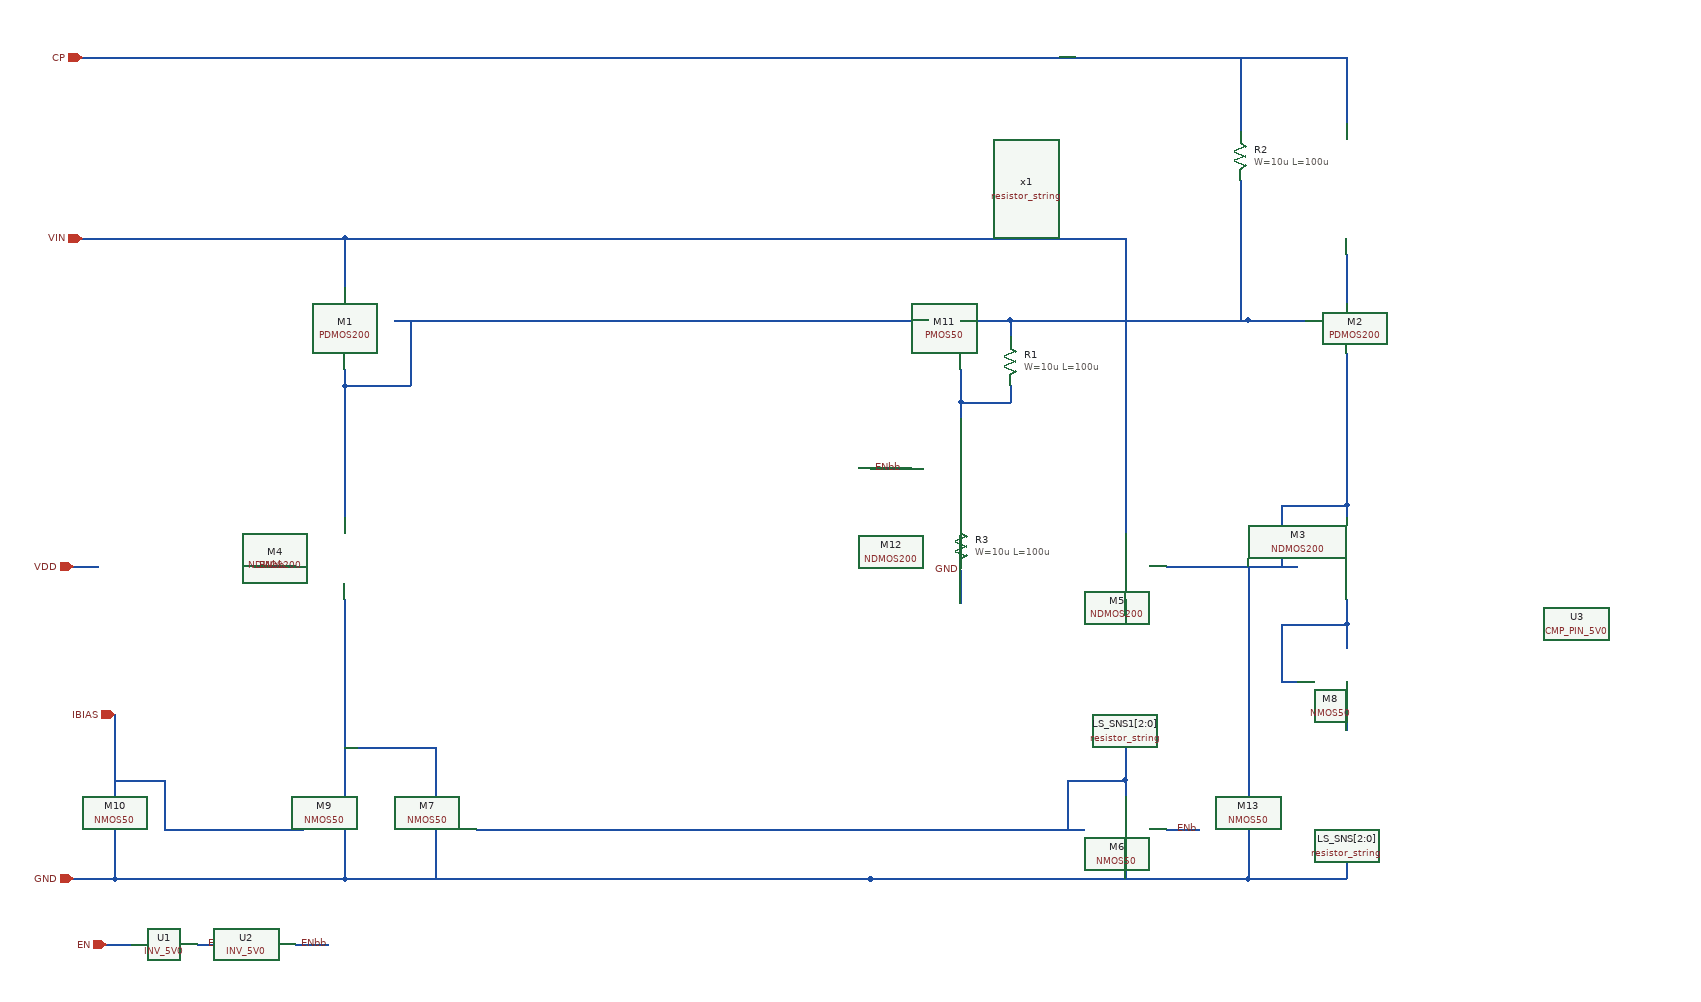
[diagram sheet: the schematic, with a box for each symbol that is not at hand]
v {xschem version=3.4.8RC file_version=1.3}
G {}
K {}
V {}
S {}
F {}
E {}
N 2680 -1240 2680 -1180 {lab=#net1}
N 1540 -1160 1540 -1080 {lab=#net2}
N 1460 -1260 1460 -1200 {lab=VIN}
N 1460 -1080 1540 -1080 {lab=#net2}
N 2680 -1480 2680 -1400 {lab=CP}
N 1970 -1480 2680 -1480 {lab=CP}
N 2600 -935 2680 -935 {lab=#net3}
N 2410 -1260 2410 -900 {lab=VIN}
N 2040 -1260 2410 -1260 {lab=VIN}
N 2460 -860 2620 -860 {lab=#net3}
N 2410 -600 2410 -580 {lab=#net4}
N 2340 -600 2410 -600 {lab=#net4}
N 2340 -600 2340 -540 {lab=#net4}
N 2410 -640 2410 -600 {lab=#net4}
N 2410 -820 2410 -800 {lab=#net5}
N 2680 -820 2680 -790 {lab=#net6}
N 2410 -540 2410 -520 {lab=GND}
N 2680 -720 2680 -680 {lab=#net7}
N 1570 -600 1570 -580 {lab=#net8}
N 1570 -640 1570 -600 {lab=#net8}
N 1570 -540 1570 -520 {lab=GND}
N 1460 -540 1460 -520 {lab=GND}
N 1570 -520 1570 -480 {lab=GND}
N 1460 -520 1460 -480 {lab=GND}
N 1460 -820 1460 -580 {lab=#net8}
N 1180 -520 1180 -500 {lab=GND}
N 1180 -540 1180 -520 {lab=GND}
N 1180 -600 1240 -600 {lab=IBIAS}
N 1240 -600 1240 -540 {lab=IBIAS}
N 2090 -540 2360 -540 {lab=#net4}
N 1460 -640 1570 -640 {lab=#net8}
N 1240 -540 1410 -540 {lab=IBIAS}
N 1180 -480 1460 -480 {lab=GND}
N 1180 -680 1180 -580 {lab=IBIAS}
N 1460 -1260 2040 -1260 {lab=VIN}
N 1620 -540 2090 -540 {lab=#net4}
N 1460 -480 2100 -480 {lab=GND}
N 1570 -480 2100 -480 {lab=GND}
N 2210 -1160 2250 -1160 {lab=#net9}
N 2270 -1160 2270 -1140 {lab=#net9}
N 2210 -1060 2270 -1060 {lab=#net10}
N 2250 -1160 2270 -1160 {lab=#net9}
N 2210 -1100 2210 -1060 {lab=#net10}
N 2550 -1480 2550 -1390 {lab=CP}
N 2550 -1160 2560 -1160 {lab=#net9}
N 2350 -1480 2550 -1480 {lab=CP}
N 2280 -1160 2290 -1160 {lab=#net9}
N 2560 -1160 2630 -1160 {lab=#net9}
N 1130 -480 1180 -480 {lab=GND}
N 1140 -1260 1460 -1260 {lab=VIN}
N 2210 -855 2210 -825 {lab=GND}
N 1130 -860 1160 -860 {lab=VDD}
N 2210 -825 2210 -815 {lab=GND}
N 2270 -1160 2280 -1160 {lab=#net9}
N 2290 -1160 2350 -1160 {lab=#net9}
N 1520 -1160 2170 -1160 {lab=#net2}
N 2560 -540 2560 -520 {lab=GND}
N 2560 -520 2560 -500 {lab=GND}
N 2410 -520 2410 -480 {lab=GND}
N 2100 -480 2430 -480 {lab=GND}
N 2430 -480 2560 -480 {lab=GND}
N 2460 -540 2500 -540 {lab=ENb}
N 2560 -860 2560 -580 {lab=#net3}
N 1170 -400 1200 -400 {lab=EN}
N 1280 -400 1320 -400 {lab=ENb}
N 1400 -400 1440 -400 {lab=ENbb}
N 1180 -600 1180 -580 {lab=IBIAS}
N 1180 -500 1180 -480 {lab=GND}
N 1460 -1100 1460 -1080 {lab=#net2}
N 1520 -1160 1540 -1160 {lab=#net2}
N 2270 -1080 2270 -1060 {lab=#net10}
N 2340 -540 2360 -540 {lab=#net4}
N 2560 -500 2560 -480 {lab=GND}
N 2600 -860 2620 -860 {lab=#net3}
N 2600 -720 2620 -720 {lab=#net6}
N 2680 -500 2680 -480 {lab=GND}
N 2560 -480 2680 -480 {lab=GND}
N 2680 -680 2680 -660 {lab=#net7}
N 2680 -790 2680 -760 {lab=#net6}
N 2600 -790 2680 -790 {lab=#net6}
N 2550 -1330 2550 -1160 {lab=#net9}
N 2350 -1160 2560 -1160 {lab=#net9}
N 1140 -1480 1970 -1480 {lab=CP}
N 2600 -935 2600 -860 {lab=#net3}
N 2680 -1120 2680 -935 {lab=#net3}
N 2680 -935 2680 -920 {lab=#net3}
N 2680 -790 2680 -760 {lab=#net6}
N 2600 -790 2600 -720 {lab=#net6}
N 2210 -1060 2210 -1040 {lab=#net10}
N 2210 -940 2210 -915 {lab=#net11}
N 2140 -980 2150 -980 {lab=ENbb}
N 2100 -980 2140 -980 {lab=ENbb}
N 1460 -1080 1460 -920 {lab=#net2}
N 1390 -860 1400 -860 {lab=ENbb}
N 1350 -860 1390 -860 {lab=ENbb}
C {designs/resistor_string.sym} 2680 -1320 0 0 {name=x1}
C {autohv/PDMOS200.sym} 1480 -1160 2 0 {name=M1 W=10u L=8u M=1 MM_SIGMA=0 spiceprefix=X}
C {autohv/PDMOS200.sym} 2660 -1160 2 1 {name=M2 W=10u L=8u M=1 MM_SIGMA=0 spiceprefix=X}
C {noconn.sym} 2730 -1280 2 0 {name=l1}
C {noconn.sym} 2730 -1320 2 0 {name=l2}
C {noconn.sym} 2730 -1360 2 0 {name=l3}
C {autohv/NDMOS200.sym} 2660 -860 0 0 {name=M3 W=10u L=8u M=1 MM_SIGMA=0 spiceprefix=X}
C {designs/resistor_string.sym} 2680 -580 0 0 {name=LS_SNS[2:0]}
C {autohv/NDMOS200.sym} 1440 -860 0 0 {name=M4 W=10u L=8u M=1 MM_SIGMA=0 spiceprefix=X}
C {autohv/NDMOS200.sym} 2430 -860 0 1 {name=M5 W=10u L=8u M=1 MM_SIGMA=0 spiceprefix=X}
C {designs/resistor_string.sym} 2410 -720 0 0 {name=LS_SNS1[2:0]}
C {noconn.sym} 2460 -740 2 0 {name=l4}
C {noconn.sym} 2460 -720 2 0 {name=l5}
C {noconn.sym} 2460 -680 2 0 {name=l6}
C {autohv/NMOS50.sym} 2390 -540 0 0 {name=M6 W=10u L=1u M=1 MM_SIGMA=0 spiceprefix=X}
C {autohv/NMOS50.sym} 2660 -720 0 0 {name=M8 W=10u L=1u M=1 MM_SIGMA=0 spiceprefix=X}
C {autohv/NMOS50.sym} 1590 -540 0 1 {name=M7 W=10u L=1u M=1 MM_SIGMA=0 spiceprefix=X}
C {autohv/NMOS50.sym} 1440 -540 0 0 {name=M9 W=10u L=1u M=1 MM_SIGMA=0 spiceprefix=X}
C {autohv/NMOS50.sym} 1200 -540 0 1 {name=M10 W=10u L=1u M=1 MM_SIGMA=0 spiceprefix=X}
C {ipin.sym} 1180 -680 1 0 {name=p3 lab=IBIAS}
C {noconn.sym} 2730 -620 2 0 {name=l7}
C {noconn.sym} 2730 -580 2 0 {name=l8}
C {noconn.sym} 2730 -540 2 0 {name=l9}
C {autohv/PMOS50.sym} 2210 -1140 3 0 {name=M11 W=10u L=1u M=1 MM_SIGMA=0 spiceprefix=X}
C {autohv/RPOLY_HI.sym} 2270 -1110 0 0 {name=R1 L=100u W=10u MM_SIGMA=0 spiceprefix=X}
C {autohv/RPOLY_HI.sym} 2550 -1360 0 0 {name=R2 L=100u W=10u MM_SIGMA=0 spiceprefix=X}
C {autohv/RPOLY_HI.sym} 2210 -885 0 0 {name=R3 L=100u W=10u MM_SIGMA=0 spiceprefix=X}
C {autohv/NDMOS200.sym} 2190 -980 0 0 {name=M12 W=10u L=8u M=1 MM_SIGMA=0 spiceprefix=X}
C {iopin.sym} 1140 -1480 2 0 {name=p5 lab=CP}
C {iopin.sym} 1140 -1260 2 0 {name=p4 lab=VIN}
C {iopin.sym} 1130 -480 2 0 {name=p1 lab=GND}
C {iopin.sym} 1130 -860 2 0 {name=p2 lab=VDD}
C {noconn.sym} 1160 -860 2 0 {name=l10}
C {lab_wire.sym} 2210 -855 3 0 {name=p6 sig_type=std_logic lab=GND}
C {lab_wire.sym} 2140 -980 0 0 {name=p10 sig_type=std_logic lab=ENbb}
C {lab_wire.sym} 1390 -860 0 0 {name=p11 sig_type=std_logic lab=ENbb}
C {autohv/NMOS50.sym} 2540 -540 0 0 {name=M13 W=10u L=1u M=1 MM_SIGMA=0 spiceprefix=X}
C {lab_wire.sym} 2500 -540 0 0 {name=p12 sig_type=std_logic lab=ENb}
C {comparators/CMP_PIN_5V0.sym} 2960 -790 0 0 {name=U3 VPWR=VDD VGND=GND spiceprefix=x IREF=5u WSCALE=1 WIN=80u LIN=2u LANA=2u FIN=1 HYSK=0}
C {logic/INV_5V0.sym} 1240 -400 0 0 {name=U1 VPWR=VDD VGND=GND spiceprefix=x}
C {ipin.sym} 1170 -400 0 0 {name=p9 lab=EN}
C {lab_wire.sym} 1320 -400 0 0 {name=p13 sig_type=std_logic lab=ENb}
C {logic/INV_5V0.sym} 1360 -400 0 0 {name=U2 VPWR=VDD VGND=GND spiceprefix=x}
C {lab_wire.sym} 1440 -400 0 0 {name=p7 sig_type=std_logic lab=ENbb}
